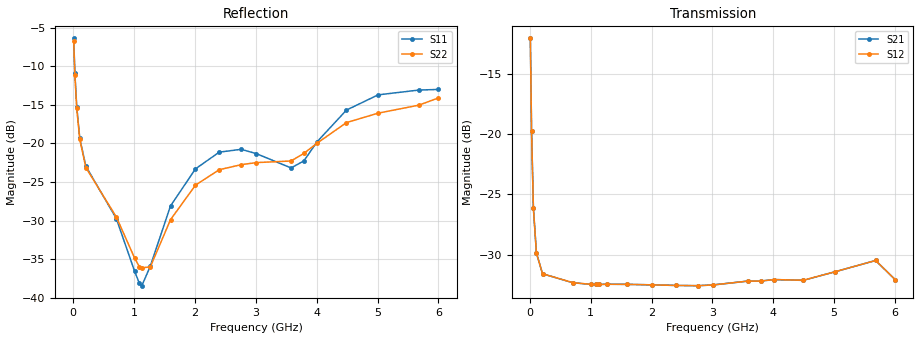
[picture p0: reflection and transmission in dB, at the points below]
! Integrated Device Technology
! Corporate Headquarters
! 6024 Silver Creek Valley Road
! San Jose, CA 95138  USA
! Phone:  1-408-284-8200
! Toll Free:  1-800-223-1366
! Webpage:  http://www.idt.com/
! Timing and RF Division
! 515 Groton Road, Suite 102
! Westford, MA 01886-6024
! Device:  F1951
! Description: 6-bit 0.5 dB Digital Step Attenuator
! Frequency:  100.0 -  4000.00 MHz
! Package:  4x4 mm Thin QFN Plastic Package: 24 pin
! Ports:  2 RF, 6 DC
!  Pin  1  = NC
!  Pin  2  = RF1  =  Port 1
!  Pin  3  = GND
!  Pin  4  = NC
!  Pin  5  = Serial Data Out (SDO)
!  Pin  6  = NC
!  Pin  7  = Reset Bar ( RSTb)
!  Pin  8  = Clock (CLK)
!  Pin  9  = Chip Select Bar (CSb)
!  Pin 10  = NC
!  Pin 11  = Serial Data In (SDI)
!  Pin 12  = NC
!  Pin 13  = NC
!  Pin 14  = VDD
!  Pin 15  = NC
!  Pin 16  = GND
!  Pin 17  = RF2  =  Port 2
!  Pin 18  = NC
!  Pin 19  = GND
!  Pin 20  = GND
!  Pin 21  = GND
!  Pin 22  = GND
!  Pin 23  = GND
!  Pin 24  = GND
! State:  63
! Atten State:  31.5 dB
! Voltage:  +3.30 Volts
! Current:  0.486 mA
! Data:  The device was measured on a F195X evaluation board which has
!  individual transmission lines to the RF pins.  Data was collected
!  de-embedded using a Automatic Fixture Removal [AFR] (Keysight Technologies).
!  The reference plane is the edge of the package pin.
! Misc:  Lot Code  1225BCA
!  Action Tracker AT0399
! Date Measured:  2018-09-13
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# GHz S dB R 50
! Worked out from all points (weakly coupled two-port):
!   600 points, 10 MHz to 6 GHz, reference 50 ohm
!   highest |S21| = -12.05 dB at 10 MHz (marker M1); lowest = -32.6 dB at 2.76 GHz (marker M2)
!   lowest |S11| = -38.4 dB at 1.13 GHz (marker M3), VSWR 1.02, Z = 48.8 + j0.222 ohm
!   |S11| at or under -10 dB: 25.4 MHz to end of sweep
!   |S22| runs from -36.5 to -6.7 dB; largest |S21 - S12| = 0.00012
!   S11 on the Smith chart (normalised r, x): 10 MHz: 1.75, -1.23; 30 MHz: 1.12, -0.61; 60 MHz: 0.98, -0.35; 1.09 GHz: 0.98, -0.00; 6 GHz: 0.81, +0.37
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0.01  -6.40 -34.6  -12.05 -45.2  -12.05 -45.2  -6.68 -35.3
0.03  -10.94 -63.1  -19.76 -68.7  -19.76 -68.8  -11.20 -62.6
0.06  -15.24 -83.1  -26.13 -62.6  -26.14 -62.5  -15.45 -82.6
0.11  -19.33 -101.0  -29.86 -44.5  -29.87 -44.5  -19.47 -100.7
0.21  -22.94 -119.4  -31.58 -27.1  -31.58 -27.1  -23.13 -119.2
0.71  -29.72 -136.3  -32.33 -13.7  -32.32 -13.8  -29.51 -138.3
1.01  -36.53 -157.9  -32.46 -13.8  -32.46 -13.8  -34.82 -153.1
1.09  -38.12 -177.8  -32.47 -13.7  -32.47 -13.7  -35.97 -163.3
1.13  -38.41 169.1  -32.47 -13.7  -32.47 -13.8  -36.11 -171.0
1.27  -35.85 131.5  -32.45 -14.3  -32.45 -14.3  -35.96 161.8
1.6  -28.09 115.0  -32.46 -16.0  -32.46 -15.9  -29.87 133.2
2.01  -23.29 122.8  -32.50 -18.6  -32.50 -18.6  -25.40 134.2
2.4  -21.13 133.1  -32.55 -20.9  -32.55 -21.0  -23.40 139.7
2.76  -20.76 141.8  -32.57 -23.1  -32.57 -23.1  -22.75 144.1
3.01  -21.32 145.5  -32.51 -24.5  -32.51 -24.4  -22.48 144.8
3.58  -23.17 124.2  -32.19 -27.8  -32.19 -27.9  -22.27 127.6
3.79  -22.26 108.5  -32.19 -29.2  -32.19 -29.2  -21.29 120.8
4.01  -19.76 100.2  -32.06 -30.7  -32.06 -30.7  -19.95 115.6
4.49  -15.68 98.7  -32.13 -33.0  -32.12 -33.0  -17.30 113.9
5.01  -13.71 107.4  -31.42 -33.3  -31.42 -33.4  -16.08 116.2
5.68  -13.09 112.5  -30.48 -45.1  -30.48 -45.1  -15.04 109.0
6  -13.01 105.9  -32.06 -43.5  -32.06 -43.5  -14.11 105.0
